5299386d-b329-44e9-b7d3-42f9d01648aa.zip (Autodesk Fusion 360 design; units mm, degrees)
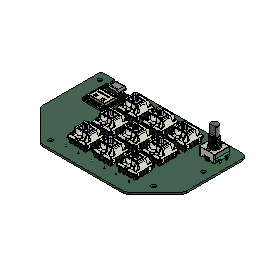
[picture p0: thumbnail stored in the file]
description: KiCad electronic assembly
part number: hackpad-san-3 1
description: Part Number
part number: Bottom
part number: Pulsador
part number: Top
part number: Pieza5^Cherry MX
part number: Pin1
part number: Pin2
part number: Led 3mm_trans
part number: Cherry MX
base_feature "Base Feature1"
base_feature "Base Feature1"
base_feature "Base Feature1"
base_feature "Base Feature1"
base_feature "Base Feature1"
base_feature "Base Feature1"
base_feature "Base Feature1"
base_feature "Base Feature1"
base_feature "Base Feature1"
base_feature "Base Feature1"
base_feature "Base Feature1"
base_feature "Base Feature1"
base_feature "Base Feature1"
base_feature "Base Feature1"
base_feature "Base Feature1"
base_feature "Base Feature1"
base_feature "Base Feature1"
base_feature "Base Feature1"
base_feature "Base Feature1"
base_feature "Base Feature1"
base_feature "Base Feature1"
base_feature "Base Feature1"
base_feature "Base Feature1"
base_feature "Base Feature1"
base_feature "Base Feature1"
base_feature "Base Feature1"
base_feature "Base Feature1"
base_feature "Base Feature1"
base_feature "Base Feature1"
base_feature "Base Feature1"
base_feature "Base Feature1"
base_feature "Base Feature1"
base_feature "Base Feature1"
base_feature "Base Feature1"
base_feature "Base Feature1"
base_feature "Base Feature1"
base_feature "Base Feature1"
base_feature "Base Feature1"
base_feature "Base Feature1"
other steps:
create_component "CreateComponent1"
create_component "CreateComponent1"
create_component "CreateComponent1"
create_component "CreateComponent2"
create_component "CreateComponent3"
create_component "CreateComponent4"
create_component "CreateComponent5"
create_component "CreateComponent6"
create_component "CreateComponent7"
create_component "CreateComponent2"
create_component "CreateComponent1"
create_component "CreateComponent1"
create_component "CreateComponent1"
create_component "CreateComponent1"
create_component "CreateComponent1"
create_component "CreateComponent2"
create_component "CreateComponent3"
create_component "CreateComponent4"
create_component "CreateComponent5"
create_component "CreateComponent6"
create_component "CreateComponent7"
create_component "CreateComponent8"
create_component "CreateComponent9"
create_component "CreateComponent10"
create_component "CreateComponent11"
create_component "CreateComponent12"
create_component "CreateComponent13"
create_component "CreateComponent14"
create_component "CreateComponent15"
create_component "CreateComponent16"
create_component "CreateComponent17"
create_component "CreateComponent18"
create_component "CreateComponent19"
create_component "CreateComponent20"
create_component "CreateComponent21"
create_component "CreateComponent22"
create_component "CreateComponent23"
create_component "CreateComponent24"
create_component "CreateComponent2"
create_component "CreateComponent3"
create_component "CreateComponent4"
create_component "CreateComponent5"
create_component "CreateComponent2"
create_component "CreateComponent3"
create_component "CreateComponent1"
create_component "CreateComponent4"
create_component "CreateComponent1"
create_component "CreateComponent5"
